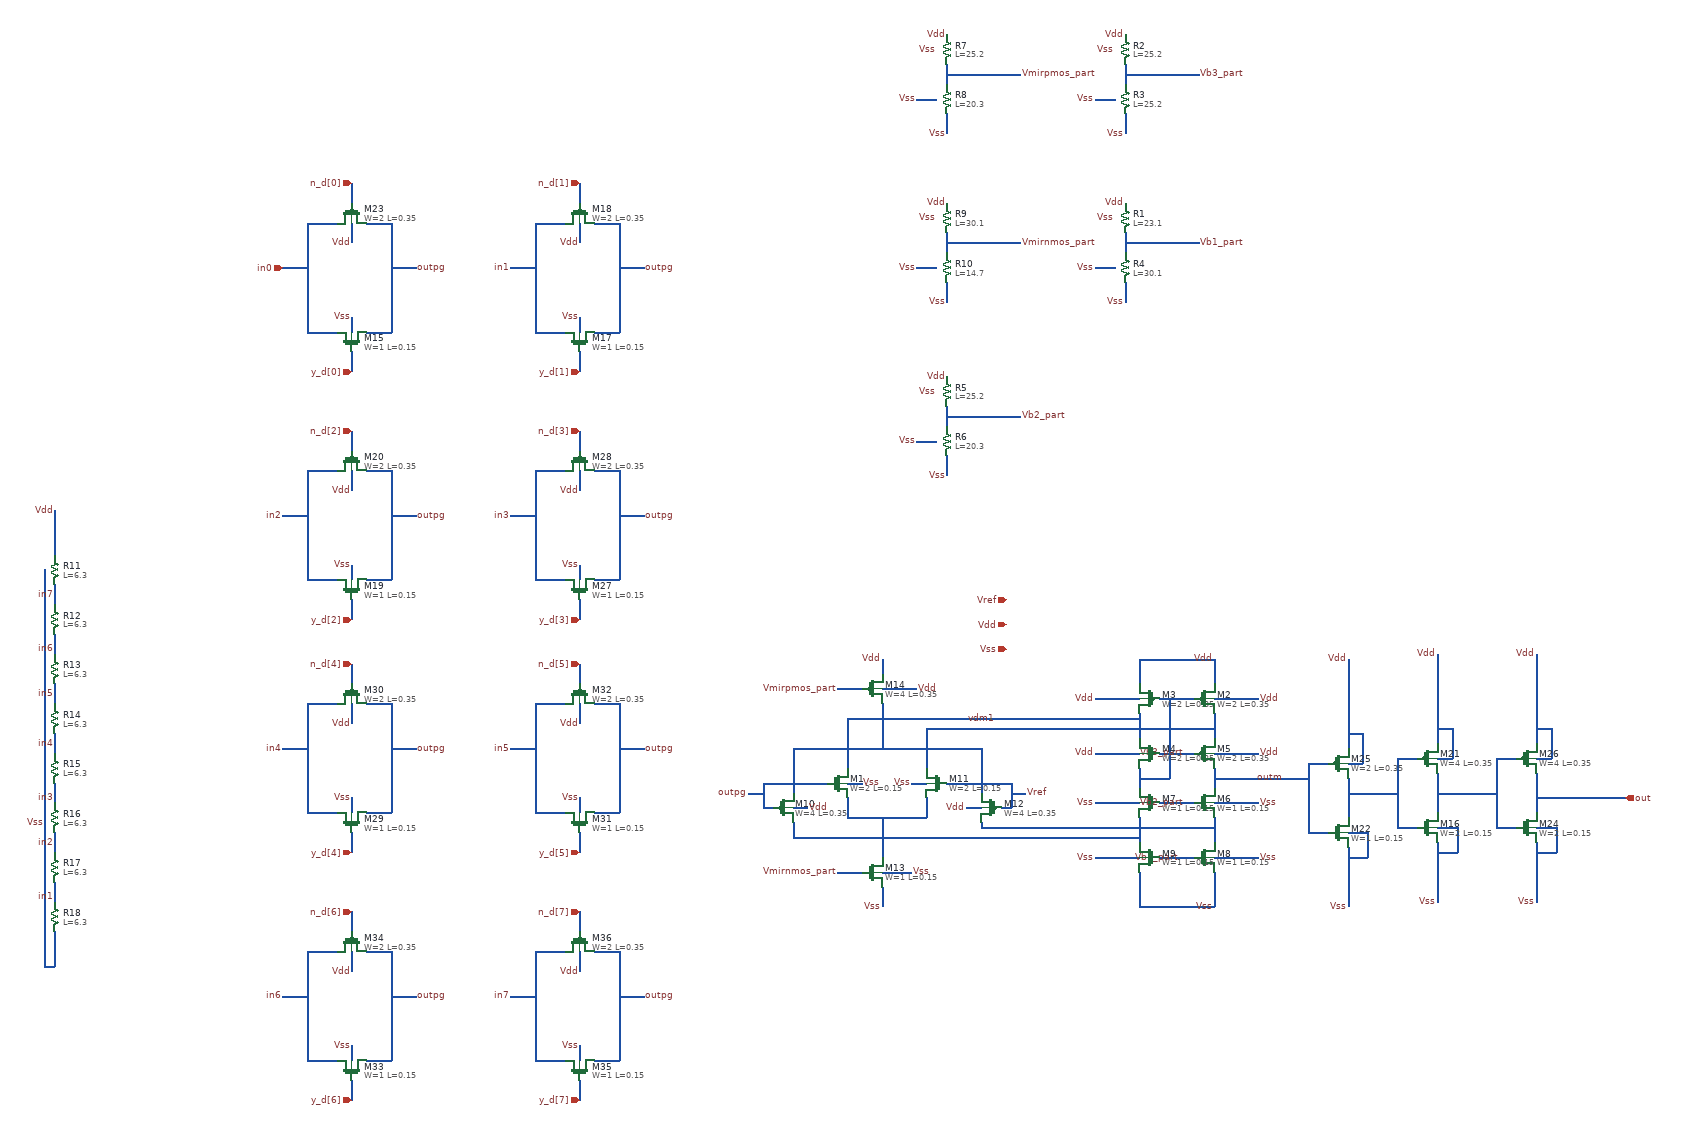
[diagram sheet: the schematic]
v {xschem version=3.4.5 file_version=1.2
}
G {}
K {}
V {}
S {}
E {}
N 430 -90 500 -90 {
lab=Vb1_part}
N 430 -200 500 -200 {
lab=Vb2_part}
N 430 -300 500 -300 {
lab=Vb3_part}
N 430 -410 500 -410 {
lab=#net1}
N 390 -380 390 -330 {
lab=vdm1}
N 390 -270 390 -230 {
lab=#net1}
N 390 -170 390 -120 {
lab=#net2}
N 540 -170 540 -120 {
lab=#net3}
N 540 -270 540 -230 {
lab=outm}
N 540 -380 540 -330 {
lab=#net4}
N 390 -490 390 -440 {
lab=#net5}
N 540 -490 540 -440 {
lab=#net5}
N 390 -60 390 10 {
lab=#net6}
N 540 -60 540 10 {
lab=#net6}
N 390 10 540 10 {
lab=#net6}
N 390 -490 540 -490 {
lab=#net5}
N -310 -310 -310 -220 {
lab=#net7}
N -310 -310 70 -310 {
lab=#net7}
N 70 -310 70 -220 {
lab=#net7}
N -200 -210 -200 -170 {
lab=#net8}
N -200 -170 -40 -170 {
lab=#net8}
N -40 -210 -40 -170 {
lab=#net8}
N -200 -370 390 -370 {
lab=vdm1}
N -200 -370 -200 -270 {
lab=vdm1}
N -40 -350 -40 -270 {
lab=#net4}
N -40 -350 540 -350 {
lab=#net4}
N 70 -160 70 -150 {
lab=#net3}
N 70 -150 540 -150 {
lab=#net3}
N -310 -160 -310 -130 {
lab=#net2}
N -310 -130 390 -130 {
lab=#net2}
N -130 -170 -130 -90 {
lab=#net8}
N -130 -400 -130 -310 {
lab=#net7}
N -130 -490 -130 -460 {
lab=#net9}
N -370 -240 -240 -240 {
lab=outpg}
N -370 -240 -370 -190 {
lab=outpg}
N -370 -190 -350 -190 {
lab=outpg}
N 0 -240 130 -240 {
lab=Vref}
N 130 -240 130 -190 {
lab=Vref}
N 110 -190 130 -190 {
lab=Vref}
N -400 -220 -370 -220 {
lab=outpg}
N 130 -220 160 -220 {
lab=Vref}
N -130 -30 -130 10 {
lab=#net10}
N 390 -250 450 -250 {
lab=#net1}
N 450 -410 450 -250 {
lab=#net1}
N -130 -60 -70 -60 {
lab=Vss}
N -130 -430 -60 -430 {
lab=Vdd}
N 40 -190 70 -190 {
lab=Vdd}
N -70 -240 -40 -240 {
lab=Vss}
N -200 -240 -170 -240 {
lab=Vss}
N -310 -190 -280 -190 {
lab=Vdd}
N 810 -250 810 -170 {
lab=#net11}
N 810 -280 840 -280 {
lab=#net12}
N 810 -140 850 -140 {
lab=#net13}
N 850 -140 850 -90 {
lab=#net13}
N 810 -90 850 -90 {
lab=#net13}
N 730 -280 770 -280 {
lab=outm}
N 730 -280 730 -140 {
lab=outm}
N 730 -140 770 -140 {
lab=outm}
N 840 -340 840 -280 {
lab=#net12}
N 810 -340 840 -340 {
lab=#net12}
N 540 -250 730 -250 {
lab=outm}
N 810 -490 810 -310 {
lab=#net12}
N 810 -110 810 10 {
lab=#net13}
N -220 -60 -170 -60 {
lab=Vmirnmos_part}
N -220 -430 -170 -430 {
lab=Vmirpmos_part}
N 300 -90 390 -90 {
lab=Vss}
N 540 -90 630 -90 {
lab=Vss}
N 300 -200 390 -200 {
lab=Vss}
N 540 -200 630 -200 {
lab=Vss}
N 540 -300 630 -300 {
lab=Vdd}
N 300 -300 390 -300 {
lab=Vdd}
N 300 -410 390 -410 {
lab=Vdd}
N 540 -410 630 -410 {
lab=Vdd}
N 360 -1690 360 -1650 {
lab=Vb3_part}
N 360 -1670 510 -1670 {
lab=Vb3_part}
N 360 -1590 360 -1550 {
lab=#net14}
N 300 -1620 340 -1620 {
lab=Vss}
N 360 -1350 360 -1310 {
lab=Vb1_part}
N 360 -1330 510 -1330 {
lab=Vb1_part}
N 360 -1250 360 -1210 {
lab=#net15}
N 300 -1280 340 -1280 {
lab=Vss}
N 0 -1000 0 -960 {
lab=Vb2_part}
N 0 -980 150 -980 {
lab=Vb2_part}
N 0 -900 0 -860 {
lab=#net16}
N -60 -930 -20 -930 {
lab=Vss}
N 0 -1690 0 -1650 {
lab=Vmirpmos_part}
N 0 -1670 150 -1670 {
lab=Vmirpmos_part}
N 0 -1590 0 -1550 {
lab=#net17}
N -60 -1620 -20 -1620 {
lab=Vss}
N 0 -1350 0 -1310 {
lab=Vmirnmos_part}
N 0 -1330 150 -1330 {
lab=Vmirnmos_part}
N 0 -1250 0 -1210 {
lab=#net18}
N -60 -1280 -20 -1280 {
lab=Vss}
N 990 -260 990 -180 {
lab=#net19}
N 990 -290 1020 -290 {
lab=#net20}
N 990 -150 1030 -150 {
lab=#net21}
N 1030 -150 1030 -100 {
lab=#net21}
N 990 -100 1030 -100 {
lab=#net21}
N 910 -290 950 -290 {
lab=#net11}
N 910 -290 910 -150 {
lab=#net11}
N 910 -150 950 -150 {
lab=#net11}
N 1020 -350 1020 -290 {
lab=#net20}
N 990 -350 1020 -350 {
lab=#net20}
N 990 -500 990 -320 {
lab=#net20}
N 990 -120 990 0 {
lab=#net21}
N 1190 -260 1190 -180 {
lab=out}
N 1190 -290 1220 -290 {
lab=#net22}
N 1190 -150 1230 -150 {
lab=#net23}
N 1230 -150 1230 -100 {
lab=#net23}
N 1190 -100 1230 -100 {
lab=#net23}
N 1110 -290 1150 -290 {
lab=#net19}
N 1110 -290 1110 -150 {
lab=#net19}
N 1110 -150 1150 -150 {
lab=#net19}
N 1220 -350 1220 -290 {
lab=#net22}
N 1190 -350 1220 -350 {
lab=#net22}
N 1190 -500 1190 -320 {
lab=#net22}
N 1190 -120 1190 0 {
lab=#net23}
N 990 -220 1110 -220 {
lab=#net19}
N 810 -220 910 -220 {
lab=#net11}
N 1190 -210 1370 -210 {
lab=out}
N -1800 -40 -1800 0 {
lab=in1}
N -1800 -140 -1800 -100 {
lab=in2}
N -1800 -240 -1800 -200 {
lab=in3}
N -1800 -340 -1800 -300 {
lab=in4}
N -1800 -440 -1800 -400 {
lab=in5}
N -1800 -540 -1800 -500 {
lab=in6}
N -1800 -640 -1800 -600 {
lab=in7}
N -1820 -670 -1820 130 {
lab=Vss}
N -1820 130 -1800 130 {
lab=Vss}
N -1800 60 -1800 130 {
lab=Vss}
N -1800 -790 -1800 -700 {
lab=Vdd}
N -1200 -1180 -1200 -1150 {
lab=Vss}
N -1170 -1370 -1120 -1370 {
lab=outpg}
N -1120 -1320 -1120 -1150 {
lab=outpg}
N -1170 -1150 -1120 -1150 {
lab=outpg}
N -1290 -1370 -1230 -1370 {
lab=in0}
N -1290 -1320 -1290 -1150 {
lab=in0}
N -1290 -1150 -1230 -1150 {
lab=in0}
N -1340 -1280 -1290 -1280 {
lab=in0}
N -1120 -1280 -1070 -1280 {
lab=outpg}
N -1200 -1450 -1200 -1410 {
lab=n_d[0]}
N -1200 -1110 -1200 -1070 {
lab=y_d[0]}
N -1200 -1370 -1200 -1330 {
lab=Vdd}
N -1290 -1370 -1290 -1320 {
lab=in0}
N -1120 -1370 -1120 -1320 {
lab=outpg}
N -740 -1180 -740 -1150 {
lab=Vss}
N -710 -1370 -660 -1370 {
lab=outpg}
N -660 -1320 -660 -1150 {
lab=outpg}
N -710 -1150 -660 -1150 {
lab=outpg}
N -830 -1370 -770 -1370 {
lab=in0}
N -830 -1320 -830 -1150 {
lab=in0}
N -830 -1150 -770 -1150 {
lab=in0}
N -880 -1280 -830 -1280 {
lab=in0}
N -660 -1280 -610 -1280 {
lab=outpg}
N -740 -1450 -740 -1410 {
lab=n_d[1]}
N -740 -1110 -740 -1070 {
lab=y_d[1]}
N -740 -1370 -740 -1330 {
lab=Vdd}
N -830 -1370 -830 -1320 {
lab=in0}
N -660 -1370 -660 -1320 {
lab=outpg}
N -1200 -680 -1200 -650 {
lab=Vss}
N -1170 -870 -1120 -870 {
lab=outpg}
N -1120 -820 -1120 -650 {
lab=outpg}
N -1170 -650 -1120 -650 {
lab=outpg}
N -1290 -870 -1230 -870 {
lab=in0}
N -1290 -820 -1290 -650 {
lab=in0}
N -1290 -650 -1230 -650 {
lab=in0}
N -1340 -780 -1290 -780 {
lab=in0}
N -1120 -780 -1070 -780 {
lab=outpg}
N -1200 -950 -1200 -910 {
lab=n_d[0]}
N -1200 -610 -1200 -570 {
lab=y_d[0]}
N -1200 -870 -1200 -830 {
lab=Vdd}
N -1290 -870 -1290 -820 {
lab=in0}
N -1120 -870 -1120 -820 {
lab=outpg}
N -740 -680 -740 -650 {
lab=Vss}
N -710 -870 -660 -870 {
lab=outpg}
N -660 -820 -660 -650 {
lab=outpg}
N -710 -650 -660 -650 {
lab=outpg}
N -830 -870 -770 -870 {
lab=in0}
N -830 -820 -830 -650 {
lab=in0}
N -830 -650 -770 -650 {
lab=in0}
N -880 -780 -830 -780 {
lab=in0}
N -660 -780 -610 -780 {
lab=outpg}
N -740 -950 -740 -910 {
lab=n_d[1]}
N -740 -610 -740 -570 {
lab=y_d[1]}
N -740 -870 -740 -830 {
lab=Vdd}
N -830 -870 -830 -820 {
lab=in0}
N -660 -870 -660 -820 {
lab=outpg}
N -1200 -210 -1200 -180 {
lab=Vss}
N -1170 -400 -1120 -400 {
lab=outpg}
N -1120 -350 -1120 -180 {
lab=outpg}
N -1170 -180 -1120 -180 {
lab=outpg}
N -1290 -400 -1230 -400 {
lab=in0}
N -1290 -350 -1290 -180 {
lab=in0}
N -1290 -180 -1230 -180 {
lab=in0}
N -1340 -310 -1290 -310 {
lab=in0}
N -1120 -310 -1070 -310 {
lab=outpg}
N -1200 -480 -1200 -440 {
lab=n_d[0]}
N -1200 -140 -1200 -100 {
lab=y_d[0]}
N -1200 -400 -1200 -360 {
lab=Vdd}
N -1290 -400 -1290 -350 {
lab=in0}
N -1120 -400 -1120 -350 {
lab=outpg}
N -740 -210 -740 -180 {
lab=Vss}
N -710 -400 -660 -400 {
lab=outpg}
N -660 -350 -660 -180 {
lab=outpg}
N -710 -180 -660 -180 {
lab=outpg}
N -830 -400 -770 -400 {
lab=in0}
N -830 -350 -830 -180 {
lab=in0}
N -830 -180 -770 -180 {
lab=in0}
N -880 -310 -830 -310 {
lab=in0}
N -660 -310 -610 -310 {
lab=outpg}
N -740 -480 -740 -440 {
lab=n_d[1]}
N -740 -140 -740 -100 {
lab=y_d[1]}
N -740 -400 -740 -360 {
lab=Vdd}
N -830 -400 -830 -350 {
lab=in0}
N -660 -400 -660 -350 {
lab=outpg}
N -1200 290 -1200 320 {
lab=Vss}
N -1170 100 -1120 100 {
lab=outpg}
N -1120 150 -1120 320 {
lab=outpg}
N -1170 320 -1120 320 {
lab=outpg}
N -1290 100 -1230 100 {
lab=in0}
N -1290 150 -1290 320 {
lab=in0}
N -1290 320 -1230 320 {
lab=in0}
N -1340 190 -1290 190 {
lab=in0}
N -1120 190 -1070 190 {
lab=outpg}
N -1200 20 -1200 60 {
lab=n_d[0]}
N -1200 360 -1200 400 {
lab=y_d[0]}
N -1200 100 -1200 140 {
lab=Vdd}
N -1290 100 -1290 150 {
lab=in0}
N -1120 100 -1120 150 {
lab=outpg}
N -740 290 -740 320 {
lab=Vss}
N -710 100 -660 100 {
lab=outpg}
N -660 150 -660 320 {
lab=outpg}
N -710 320 -660 320 {
lab=outpg}
N -830 100 -770 100 {
lab=in0}
N -830 150 -830 320 {
lab=in0}
N -830 320 -770 320 {
lab=in0}
N -880 190 -830 190 {
lab=in0}
N -660 190 -610 190 {
lab=outpg}
N -740 20 -740 60 {
lab=n_d[1]}
N -740 360 -740 400 {
lab=y_d[1]}
N -740 100 -740 140 {
lab=Vdd}
N -830 100 -830 150 {
lab=in0}
N -660 100 -660 150 {
lab=outpg}
C {sky130_fd_pr/nfet_01v8_lvt.sym} -220 -240 0 0 {name=M1
L=0.15
W=2
nf=2
mult=1
ad="'int((nf+1)/2) * W/nf * 0.29'" 
pd="'2*int((nf+1)/2) * (W/nf + 0.29)'"
as="'int((nf+2)/2) * W/nf * 0.29'" 
ps="'2*int((nf+2)/2) * (W/nf + 0.29)'"
nrd="'0.29 / W'" nrs="'0.29 / W'"
sa=0 sb=0 sd=0
model=nfet_01v8_lvt
spiceprefix=X
}
C {sky130_fd_pr/pfet_01v8_lvt.sym} 410 -410 0 1 {name=M3
L=0.35
W=2
nf=2
mult=1
ad="'int((nf+1)/2) * W/nf * 0.29'" 
pd="'2*int((nf+1)/2) * (W/nf + 0.29)'"
as="'int((nf+2)/2) * W/nf * 0.29'" 
ps="'2*int((nf+2)/2) * (W/nf + 0.29)'"
nrd="'0.29 / W'" nrs="'0.29 / W'"
sa=0 sb=0 sd=0
model=pfet_01v8_lvt
spiceprefix=X
}
C {sky130_fd_pr/nfet_01v8_lvt.sym} 410 -200 0 1 {name=M7
L=0.15
W=1
nf=1
mult=1
ad="'int((nf+1)/2) * W/nf * 0.29'" 
pd="'2*int((nf+1)/2) * (W/nf + 0.29)'"
as="'int((nf+2)/2) * W/nf * 0.29'" 
ps="'2*int((nf+2)/2) * (W/nf + 0.29)'"
nrd="'0.29 / W'" nrs="'0.29 / W'"
sa=0 sb=0 sd=0
model=nfet_01v8_lvt
spiceprefix=X
}
C {devices/lab_wire.sym} 300 -300 0 0 {name=p1 sig_type=std_logic lab=Vdd}
C {devices/lab_wire.sym} 300 -410 0 0 {name=p2 sig_type=std_logic lab=Vdd}
C {devices/lab_wire.sym} 630 -410 0 1 {name=p3 sig_type=std_logic lab=Vdd}
C {devices/lab_wire.sym} 630 -300 0 1 {name=p4 sig_type=std_logic lab=Vdd}
C {devices/lab_wire.sym} 300 -200 0 0 {name=p5 sig_type=std_logic lab=Vss}
C {devices/lab_wire.sym} 300 -90 0 0 {name=p6 sig_type=std_logic lab=Vss}
C {devices/lab_wire.sym} 630 -90 0 1 {name=p7 sig_type=std_logic lab=Vss}
C {devices/lab_wire.sym} 630 -200 0 1 {name=p8 sig_type=std_logic lab=Vss}
C {devices/lab_wire.sym} 480 -300 0 0 {name=p13 sig_type=std_logic lab=Vb3_part}
C {devices/lab_wire.sym} 480 -200 0 0 {name=p14 sig_type=std_logic lab=Vb2_part}
C {devices/lab_wire.sym} 470 -90 0 0 {name=p16 sig_type=std_logic lab=Vb1_part}
C {devices/lab_wire.sym} 540 10 0 0 {name=p17 sig_type=std_logic lab=Vss}
C {devices/lab_wire.sym} 540 -490 0 0 {name=p18 sig_type=std_logic lab=Vdd}
C {sky130_fd_pr/pfet_01v8_lvt.sym} -330 -190 0 0 {name=M10
L=0.35
W=4
nf=4
mult=1
ad="'int((nf+1)/2) * W/nf * 0.29'" 
pd="'2*int((nf+1)/2) * (W/nf + 0.29)'"
as="'int((nf+2)/2) * W/nf * 0.29'" 
ps="'2*int((nf+2)/2) * (W/nf + 0.29)'"
nrd="'0.29 / W'" nrs="'0.29 / W'"
sa=0 sb=0 sd=0
model=pfet_01v8_lvt
spiceprefix=X
}
C {sky130_fd_pr/nfet_01v8_lvt.sym} -20 -240 0 1 {name=M11
L=0.15
W=2
nf=2
mult=1
ad="'int((nf+1)/2) * W/nf * 0.29'" 
pd="'2*int((nf+1)/2) * (W/nf + 0.29)'"
as="'int((nf+2)/2) * W/nf * 0.29'" 
ps="'2*int((nf+2)/2) * (W/nf + 0.29)'"
nrd="'0.29 / W'" nrs="'0.29 / W'"
sa=0 sb=0 sd=0
model=nfet_01v8_lvt
spiceprefix=X
}
C {sky130_fd_pr/pfet_01v8_lvt.sym} 90 -190 0 1 {name=M12
L=0.35
W=4
nf=4
mult=1
ad="'int((nf+1)/2) * W/nf * 0.29'" 
pd="'2*int((nf+1)/2) * (W/nf + 0.29)'"
as="'int((nf+2)/2) * W/nf * 0.29'" 
ps="'2*int((nf+2)/2) * (W/nf + 0.29)'"
nrd="'0.29 / W'" nrs="'0.29 / W'"
sa=0 sb=0 sd=0
model=pfet_01v8_lvt
spiceprefix=X
}
C {sky130_fd_pr/nfet_01v8_lvt.sym} -150 -60 0 0 {name=M13
L=0.15
W=1
nf=1
mult=1
ad="'int((nf+1)/2) * W/nf * 0.29'" 
pd="'2*int((nf+1)/2) * (W/nf + 0.29)'"
as="'int((nf+2)/2) * W/nf * 0.29'" 
ps="'2*int((nf+2)/2) * (W/nf + 0.29)'"
nrd="'0.29 / W'" nrs="'0.29 / W'"
sa=0 sb=0 sd=0
model=nfet_01v8_lvt
spiceprefix=X
}
C {sky130_fd_pr/pfet_01v8_lvt.sym} -150 -430 0 0 {name=M14
L=0.35
W=4
nf=4
mult=1
ad="'int((nf+1)/2) * W/nf * 0.29'" 
pd="'2*int((nf+1)/2) * (W/nf + 0.29)'"
as="'int((nf+2)/2) * W/nf * 0.29'" 
ps="'2*int((nf+2)/2) * (W/nf + 0.29)'"
nrd="'0.29 / W'" nrs="'0.29 / W'"
sa=0 sb=0 sd=0
model=pfet_01v8_lvt
spiceprefix=X
}
C {devices/lab_wire.sym} -130 -490 0 0 {name=p19 sig_type=std_logic lab=Vdd}
C {devices/lab_wire.sym} -130 10 0 0 {name=p20 sig_type=std_logic lab=Vss}
C {devices/lab_wire.sym} 160 -220 0 1 {name=p22 sig_type=std_logic lab=Vref}
C {devices/opin.sym} 1370 -210 0 0 {name=p24 lab=out}
C {devices/lab_wire.sym} -60 -430 0 1 {name=p26 sig_type=std_logic lab=Vdd}
C {devices/lab_wire.sym} -70 -60 0 1 {name=p28 sig_type=std_logic lab=Vss}
C {devices/lab_wire.sym} -170 -240 0 1 {name=p29 sig_type=std_logic lab=Vss}
C {devices/lab_wire.sym} -70 -240 0 0 {name=p30 sig_type=std_logic lab=Vss}
C {devices/lab_wire.sym} -280 -190 0 1 {name=p31 sig_type=std_logic lab=Vdd}
C {devices/lab_wire.sym} 40 -190 0 0 {name=p32 sig_type=std_logic lab=Vdd}
C {sky130_fd_pr/nfet_01v8_lvt.sym} 790 -140 0 0 {name=M22
L=0.15
W=1
nf=1
mult=1
ad="'int((nf+1)/2) * W/nf * 0.29'" 
pd="'2*int((nf+1)/2) * (W/nf + 0.29)'"
as="'int((nf+2)/2) * W/nf * 0.29'" 
ps="'2*int((nf+2)/2) * (W/nf + 0.29)'"
nrd="'0.29 / W'" nrs="'0.29 / W'"
sa=0 sb=0 sd=0
model=nfet_01v8_lvt
spiceprefix=X
}
C {sky130_fd_pr/pfet_01v8_lvt.sym} 790 -280 0 0 {name=M25
L=0.35
W=2
nf=2
mult=1
ad="'int((nf+1)/2) * W/nf * 0.29'" 
pd="'2*int((nf+1)/2) * (W/nf + 0.29)'"
as="'int((nf+2)/2) * W/nf * 0.29'" 
ps="'2*int((nf+2)/2) * (W/nf + 0.29)'"
nrd="'0.29 / W'" nrs="'0.29 / W'"
sa=0 sb=0 sd=0
model=pfet_01v8_lvt
spiceprefix=X
}
C {devices/lab_wire.sym} 680 -250 0 0 {name=p9 sig_type=std_logic lab=outm}
C {devices/lab_wire.sym} 100 -370 0 0 {name=p37 sig_type=std_logic lab=vdm1}
C {devices/lab_wire.sym} -220 -430 0 0 {name=p39 sig_type=std_logic lab=Vmirpmos_part}
C {devices/lab_wire.sym} -220 -60 0 0 {name=p41 sig_type=std_logic lab=Vmirnmos_part}
C {sky130_fd_pr/res_high_po_0p35.sym} 360 -1720 0 0 {name=R2
L=25.2
model=res_high_po_0p35
spiceprefix=X
mult=1}
C {devices/lab_wire.sym} 340 -1720 0 0 {name=p35 sig_type=std_logic lab=Vss}
C {devices/lab_wire.sym} 360 -1750 0 0 {name=p36 sig_type=std_logic lab=Vdd}
C {devices/lab_wire.sym} 510 -1670 0 1 {name=p42 sig_type=std_logic lab=Vb3_part}
C {devices/lab_wire.sym} 360 -1550 3 0 {name=p43 sig_type=std_logic lab=Vss}
C {devices/lab_wire.sym} 300 -1620 0 0 {name=p55 sig_type=std_logic lab=Vss}
C {sky130_fd_pr/res_high_po_0p35.sym} 360 -1620 0 0 {name=R3
L=25.2
model=res_high_po_0p35
spiceprefix=X
mult=1}
C {sky130_fd_pr/res_high_po_0p35.sym} 360 -1380 0 0 {name=R1
L=23.1
model=res_high_po_0p35
spiceprefix=X
mult=1}
C {devices/lab_wire.sym} 340 -1380 0 0 {name=p23 sig_type=std_logic lab=Vss}
C {devices/lab_wire.sym} 360 -1410 0 0 {name=p25 sig_type=std_logic lab=Vdd}
C {devices/lab_wire.sym} 510 -1330 0 1 {name=p27 sig_type=std_logic lab=Vb1_part}
C {devices/lab_wire.sym} 360 -1210 3 0 {name=p33 sig_type=std_logic lab=Vss}
C {devices/lab_wire.sym} 300 -1280 0 0 {name=p34 sig_type=std_logic lab=Vss}
C {sky130_fd_pr/res_high_po_0p35.sym} 360 -1280 0 0 {name=R4
L=30.1
model=res_high_po_0p35
spiceprefix=X
mult=1}
C {sky130_fd_pr/res_high_po_0p35.sym} 0 -1030 0 0 {name=R5
L=25.2
model=res_high_po_0p35
spiceprefix=X
mult=1}
C {devices/lab_wire.sym} -20 -1030 0 0 {name=p56 sig_type=std_logic lab=Vss}
C {devices/lab_wire.sym} 0 -1060 0 0 {name=p58 sig_type=std_logic lab=Vdd}
C {devices/lab_wire.sym} 150 -980 0 1 {name=p59 sig_type=std_logic lab=Vb2_part}
C {devices/lab_wire.sym} 0 -860 3 0 {name=p60 sig_type=std_logic lab=Vss}
C {devices/lab_wire.sym} -60 -930 0 0 {name=p61 sig_type=std_logic lab=Vss}
C {sky130_fd_pr/res_high_po_0p35.sym} 0 -930 0 0 {name=R6
L=20.3
model=res_high_po_0p35
spiceprefix=X
mult=1}
C {sky130_fd_pr/res_high_po_0p35.sym} 0 -1720 0 0 {name=R7
L=25.2
model=res_high_po_0p35
spiceprefix=X
mult=1}
C {devices/lab_wire.sym} -20 -1720 0 0 {name=p62 sig_type=std_logic lab=Vss}
C {devices/lab_wire.sym} 0 -1750 0 0 {name=p63 sig_type=std_logic lab=Vdd}
C {devices/lab_wire.sym} 150 -1670 0 1 {name=p64 sig_type=std_logic lab=Vmirpmos_part}
C {devices/lab_wire.sym} 0 -1550 3 0 {name=p65 sig_type=std_logic lab=Vss}
C {devices/lab_wire.sym} -60 -1620 0 0 {name=p66 sig_type=std_logic lab=Vss}
C {sky130_fd_pr/res_high_po_0p35.sym} 0 -1620 0 0 {name=R8
L=20.3
model=res_high_po_0p35
spiceprefix=X
mult=1}
C {sky130_fd_pr/res_high_po_0p35.sym} 0 -1380 0 0 {name=R9
L=30.1
model=res_high_po_0p35
spiceprefix=X
mult=1}
C {devices/lab_wire.sym} -20 -1380 0 0 {name=p67 sig_type=std_logic lab=Vss}
C {devices/lab_wire.sym} 0 -1410 0 0 {name=p68 sig_type=std_logic lab=Vdd}
C {devices/lab_wire.sym} 150 -1330 0 1 {name=p69 sig_type=std_logic lab=Vmirnmos_part}
C {devices/lab_wire.sym} 0 -1210 3 0 {name=p70 sig_type=std_logic lab=Vss}
C {devices/lab_wire.sym} -60 -1280 0 0 {name=p71 sig_type=std_logic lab=Vss}
C {sky130_fd_pr/res_high_po_0p35.sym} 0 -1280 0 0 {name=R10
L=14.7
model=res_high_po_0p35
spiceprefix=X
mult=1}
C {devices/lab_wire.sym} 810 -490 0 0 {name=p74 sig_type=std_logic lab=Vdd}
C {devices/lab_wire.sym} 810 10 0 0 {name=p75 sig_type=std_logic lab=Vss}
C {devices/lab_wire.sym} -400 -220 0 0 {name=p79 sig_type=std_logic lab=outpg}
C {sky130_fd_pr/nfet_01v8_lvt.sym} 970 -150 0 0 {name=M16
L=0.15
W=2
nf=2
mult=1
ad="'int((nf+1)/2) * W/nf * 0.29'" 
pd="'2*int((nf+1)/2) * (W/nf + 0.29)'"
as="'int((nf+2)/2) * W/nf * 0.29'" 
ps="'2*int((nf+2)/2) * (W/nf + 0.29)'"
nrd="'0.29 / W'" nrs="'0.29 / W'"
sa=0 sb=0 sd=0
model=nfet_01v8_lvt
spiceprefix=X
}
C {sky130_fd_pr/pfet_01v8_lvt.sym} 970 -290 0 0 {name=M21
L=0.35
W=4
nf=4
mult=1
ad="'int((nf+1)/2) * W/nf * 0.29'" 
pd="'2*int((nf+1)/2) * (W/nf + 0.29)'"
as="'int((nf+2)/2) * W/nf * 0.29'" 
ps="'2*int((nf+2)/2) * (W/nf + 0.29)'"
nrd="'0.29 / W'" nrs="'0.29 / W'"
sa=0 sb=0 sd=0
model=pfet_01v8_lvt
spiceprefix=X
}
C {devices/lab_wire.sym} 990 0 0 0 {name=p85 sig_type=std_logic lab=Vss}
C {sky130_fd_pr/nfet_01v8_lvt.sym} 1170 -150 0 0 {name=M24
L=0.15
W=2
nf=2
mult=1
ad="'int((nf+1)/2) * W/nf * 0.29'" 
pd="'2*int((nf+1)/2) * (W/nf + 0.29)'"
as="'int((nf+2)/2) * W/nf * 0.29'" 
ps="'2*int((nf+2)/2) * (W/nf + 0.29)'"
nrd="'0.29 / W'" nrs="'0.29 / W'"
sa=0 sb=0 sd=0
model=nfet_01v8_lvt
spiceprefix=X
}
C {sky130_fd_pr/pfet_01v8_lvt.sym} 1170 -290 0 0 {name=M26
L=0.35
W=4
nf=4
mult=1
ad="'int((nf+1)/2) * W/nf * 0.29'" 
pd="'2*int((nf+1)/2) * (W/nf + 0.29)'"
as="'int((nf+2)/2) * W/nf * 0.29'" 
ps="'2*int((nf+2)/2) * (W/nf + 0.29)'"
nrd="'0.29 / W'" nrs="'0.29 / W'"
sa=0 sb=0 sd=0
model=pfet_01v8_lvt
spiceprefix=X
}
C {devices/lab_wire.sym} 1190 0 0 0 {name=p88 sig_type=std_logic lab=Vss}
C {devices/lab_wire.sym} 990 -500 0 0 {name=p57 sig_type=std_logic lab=Vdd}
C {devices/lab_wire.sym} 1190 -500 0 0 {name=p89 sig_type=std_logic lab=Vdd}
C {sky130_fd_pr/pfet_01v8_lvt.sym} 520 -410 0 0 {name=M2
L=0.35
W=2
nf=2
mult=1
ad="'int((nf+1)/2) * W/nf * 0.29'" 
pd="'2*int((nf+1)/2) * (W/nf + 0.29)'"
as="'int((nf+2)/2) * W/nf * 0.29'" 
ps="'2*int((nf+2)/2) * (W/nf + 0.29)'"
nrd="'0.29 / W'" nrs="'0.29 / W'"
sa=0 sb=0 sd=0
model=pfet_01v8_lvt
spiceprefix=X
}
C {sky130_fd_pr/pfet_01v8_lvt.sym} 410 -300 0 1 {name=M4
L=0.35
W=2
nf=2
mult=1
ad="'int((nf+1)/2) * W/nf * 0.29'" 
pd="'2*int((nf+1)/2) * (W/nf + 0.29)'"
as="'int((nf+2)/2) * W/nf * 0.29'" 
ps="'2*int((nf+2)/2) * (W/nf + 0.29)'"
nrd="'0.29 / W'" nrs="'0.29 / W'"
sa=0 sb=0 sd=0
model=pfet_01v8_lvt
spiceprefix=X
}
C {sky130_fd_pr/pfet_01v8_lvt.sym} 520 -300 0 0 {name=M5
L=0.35
W=2
nf=2
mult=1
ad="'int((nf+1)/2) * W/nf * 0.29'" 
pd="'2*int((nf+1)/2) * (W/nf + 0.29)'"
as="'int((nf+2)/2) * W/nf * 0.29'" 
ps="'2*int((nf+2)/2) * (W/nf + 0.29)'"
nrd="'0.29 / W'" nrs="'0.29 / W'"
sa=0 sb=0 sd=0
model=pfet_01v8_lvt
spiceprefix=X
}
C {sky130_fd_pr/nfet_01v8_lvt.sym} 520 -200 0 0 {name=M6
L=0.15
W=1
nf=1
mult=1
ad="'int((nf+1)/2) * W/nf * 0.29'" 
pd="'2*int((nf+1)/2) * (W/nf + 0.29)'"
as="'int((nf+2)/2) * W/nf * 0.29'" 
ps="'2*int((nf+2)/2) * (W/nf + 0.29)'"
nrd="'0.29 / W'" nrs="'0.29 / W'"
sa=0 sb=0 sd=0
model=nfet_01v8_lvt
spiceprefix=X
}
C {sky130_fd_pr/nfet_01v8_lvt.sym} 520 -90 0 0 {name=M8
L=0.15
W=1
nf=1
mult=1
ad="'int((nf+1)/2) * W/nf * 0.29'" 
pd="'2*int((nf+1)/2) * (W/nf + 0.29)'"
as="'int((nf+2)/2) * W/nf * 0.29'" 
ps="'2*int((nf+2)/2) * (W/nf + 0.29)'"
nrd="'0.29 / W'" nrs="'0.29 / W'"
sa=0 sb=0 sd=0
model=nfet_01v8_lvt
spiceprefix=X
}
C {sky130_fd_pr/nfet_01v8_lvt.sym} 410 -90 0 1 {name=M9
L=0.15
W=1
nf=1
mult=1
ad="'int((nf+1)/2) * W/nf * 0.29'" 
pd="'2*int((nf+1)/2) * (W/nf + 0.29)'"
as="'int((nf+2)/2) * W/nf * 0.29'" 
ps="'2*int((nf+2)/2) * (W/nf + 0.29)'"
nrd="'0.29 / W'" nrs="'0.29 / W'"
sa=0 sb=0 sd=0
model=nfet_01v8_lvt
spiceprefix=X
}
C {devices/ipin.sym} 120 -560 0 0 {name=p10 lab=Vdd}
C {devices/ipin.sym} 120 -510 0 0 {name=p11 lab=Vss}
C {devices/lab_wire.sym} -1820 -160 0 0 {name=p95 sig_type=std_logic lab=Vss}
C {devices/lab_wire.sym} -1800 -790 0 0 {name=p97 sig_type=std_logic lab=Vdd}
C {devices/lab_wire.sym} -1800 -10 0 0 {name=p103 sig_type=std_logic lab=in1}
C {devices/lab_wire.sym} -1800 -120 0 0 {name=p104 sig_type=std_logic lab=in2
}
C {devices/lab_wire.sym} -1800 -210 0 0 {name=p105 sig_type=std_logic lab=in3}
C {devices/lab_wire.sym} -1800 -320 0 0 {name=p106 sig_type=std_logic lab=in4}
C {devices/lab_wire.sym} -1800 -420 0 0 {name=p107 sig_type=std_logic lab=in5}
C {devices/lab_wire.sym} -1800 -510 0 0 {name=p108 sig_type=std_logic lab=in6}
C {devices/lab_wire.sym} -1800 -620 0 0 {name=p109 sig_type=std_logic lab=in7}
C {sky130_fd_pr/res_high_po_0p35.sym} -1800 -670 0 0 {name=R11
L=6.3
model=res_high_po_0p35
spiceprefix=X
mult=1}
C {sky130_fd_pr/res_high_po_0p35.sym} -1800 -570 0 0 {name=R12
L=6.3
model=res_high_po_0p35
spiceprefix=X
mult=1}
C {sky130_fd_pr/res_high_po_0p35.sym} -1800 -470 0 0 {name=R13
L=6.3
model=res_high_po_0p35
spiceprefix=X
mult=1}
C {sky130_fd_pr/res_high_po_0p35.sym} -1800 -370 0 0 {name=R14
L=6.3
model=res_high_po_0p35
spiceprefix=X
mult=1}
C {sky130_fd_pr/res_high_po_0p35.sym} -1800 -270 0 0 {name=R15
L=6.3
model=res_high_po_0p35
spiceprefix=X
mult=1}
C {sky130_fd_pr/res_high_po_0p35.sym} -1800 -170 0 0 {name=R16
L=6.3
model=res_high_po_0p35
spiceprefix=X
mult=1}
C {sky130_fd_pr/res_high_po_0p35.sym} -1800 -70 0 0 {name=R17
L=6.3
model=res_high_po_0p35
spiceprefix=X
mult=1}
C {sky130_fd_pr/res_high_po_0p35.sym} -1800 30 0 0 {name=R18
L=6.3
model=res_high_po_0p35
spiceprefix=X
mult=1}
C {devices/ipin.sym} 120 -610 0 0 {name=p12 lab=Vref}
C {sky130_fd_pr/nfet_01v8_lvt.sym} -1200 -1130 3 0 {name=M15
L=0.15
W=1
nf=1
mult=1
ad="'int((nf+1)/2) * W/nf * 0.29'" 
pd="'2*int((nf+1)/2) * (W/nf + 0.29)'"
as="'int((nf+2)/2) * W/nf * 0.29'" 
ps="'2*int((nf+2)/2) * (W/nf + 0.29)'"
nrd="'0.29 / W'" nrs="'0.29 / W'"
sa=0 sb=0 sd=0
model=nfet_01v8_lvt
spiceprefix=X
}
C {sky130_fd_pr/pfet_01v8_lvt.sym} -1200 -1390 3 1 {name=M23
L=0.35
W=2
nf=2
mult=1
ad="'int((nf+1)/2) * W/nf * 0.29'" 
pd="'2*int((nf+1)/2) * (W/nf + 0.29)'"
as="'int((nf+2)/2) * W/nf * 0.29'" 
ps="'2*int((nf+2)/2) * (W/nf + 0.29)'"
nrd="'0.29 / W'" nrs="'0.29 / W'"
sa=0 sb=0 sd=0
model=pfet_01v8_lvt
spiceprefix=X
}
C {devices/ipin.sym} -1200 -1450 0 0 {name=p111 lab=n_d[0]}
C {devices/ipin.sym} -1200 -1070 0 0 {name=p114 lab=y_d[0]}
C {devices/ipin.sym} -1340 -1280 0 0 {name=p38 lab=in0}
C {sky130_fd_pr/nfet_01v8_lvt.sym} -740 -1130 3 0 {name=M17
L=0.15
W=1
nf=1
mult=1
ad="'int((nf+1)/2) * W/nf * 0.29'" 
pd="'2*int((nf+1)/2) * (W/nf + 0.29)'"
as="'int((nf+2)/2) * W/nf * 0.29'" 
ps="'2*int((nf+2)/2) * (W/nf + 0.29)'"
nrd="'0.29 / W'" nrs="'0.29 / W'"
sa=0 sb=0 sd=0
model=nfet_01v8_lvt
spiceprefix=X
}
C {sky130_fd_pr/pfet_01v8_lvt.sym} -740 -1390 3 1 {name=M18
L=0.35
W=2
nf=2
mult=1
ad="'int((nf+1)/2) * W/nf * 0.29'" 
pd="'2*int((nf+1)/2) * (W/nf + 0.29)'"
as="'int((nf+2)/2) * W/nf * 0.29'" 
ps="'2*int((nf+2)/2) * (W/nf + 0.29)'"
nrd="'0.29 / W'" nrs="'0.29 / W'"
sa=0 sb=0 sd=0
model=pfet_01v8_lvt
spiceprefix=X
}
C {devices/ipin.sym} -740 -1450 0 0 {name=p44 lab=n_d[1]}
C {devices/ipin.sym} -740 -1070 0 0 {name=p45 lab=y_d[1]}
C {sky130_fd_pr/nfet_01v8_lvt.sym} -1200 -630 3 0 {name=M19
L=0.15
W=1
nf=1
mult=1
ad="'int((nf+1)/2) * W/nf * 0.29'" 
pd="'2*int((nf+1)/2) * (W/nf + 0.29)'"
as="'int((nf+2)/2) * W/nf * 0.29'" 
ps="'2*int((nf+2)/2) * (W/nf + 0.29)'"
nrd="'0.29 / W'" nrs="'0.29 / W'"
sa=0 sb=0 sd=0
model=nfet_01v8_lvt
spiceprefix=X
}
C {sky130_fd_pr/pfet_01v8_lvt.sym} -1200 -890 3 1 {name=M20
L=0.35
W=2
nf=2
mult=1
ad="'int((nf+1)/2) * W/nf * 0.29'" 
pd="'2*int((nf+1)/2) * (W/nf + 0.29)'"
as="'int((nf+2)/2) * W/nf * 0.29'" 
ps="'2*int((nf+2)/2) * (W/nf + 0.29)'"
nrd="'0.29 / W'" nrs="'0.29 / W'"
sa=0 sb=0 sd=0
model=pfet_01v8_lvt
spiceprefix=X
}
C {devices/ipin.sym} -1200 -950 0 0 {name=p50 lab=n_d[2]}
C {devices/ipin.sym} -1200 -570 0 0 {name=p51 lab=y_d[2]}
C {sky130_fd_pr/nfet_01v8_lvt.sym} -740 -630 3 0 {name=M27
L=0.15
W=1
nf=1
mult=1
ad="'int((nf+1)/2) * W/nf * 0.29'" 
pd="'2*int((nf+1)/2) * (W/nf + 0.29)'"
as="'int((nf+2)/2) * W/nf * 0.29'" 
ps="'2*int((nf+2)/2) * (W/nf + 0.29)'"
nrd="'0.29 / W'" nrs="'0.29 / W'"
sa=0 sb=0 sd=0
model=nfet_01v8_lvt
spiceprefix=X
}
C {sky130_fd_pr/pfet_01v8_lvt.sym} -740 -890 3 1 {name=M28
L=0.35
W=2
nf=2
mult=1
ad="'int((nf+1)/2) * W/nf * 0.29'" 
pd="'2*int((nf+1)/2) * (W/nf + 0.29)'"
as="'int((nf+2)/2) * W/nf * 0.29'" 
ps="'2*int((nf+2)/2) * (W/nf + 0.29)'"
nrd="'0.29 / W'" nrs="'0.29 / W'"
sa=0 sb=0 sd=0
model=pfet_01v8_lvt
spiceprefix=X
}
C {devices/ipin.sym} -740 -950 0 0 {name=p73 lab=n_d[3]}
C {devices/ipin.sym} -740 -570 0 0 {name=p76 lab=y_d[3]}
C {sky130_fd_pr/nfet_01v8_lvt.sym} -1200 -160 3 0 {name=M29
L=0.15
W=1
nf=1
mult=1
ad="'int((nf+1)/2) * W/nf * 0.29'" 
pd="'2*int((nf+1)/2) * (W/nf + 0.29)'"
as="'int((nf+2)/2) * W/nf * 0.29'" 
ps="'2*int((nf+2)/2) * (W/nf + 0.29)'"
nrd="'0.29 / W'" nrs="'0.29 / W'"
sa=0 sb=0 sd=0
model=nfet_01v8_lvt
spiceprefix=X
}
C {sky130_fd_pr/pfet_01v8_lvt.sym} -1200 -420 3 1 {name=M30
L=0.35
W=2
nf=2
mult=1
ad="'int((nf+1)/2) * W/nf * 0.29'" 
pd="'2*int((nf+1)/2) * (W/nf + 0.29)'"
as="'int((nf+2)/2) * W/nf * 0.29'" 
ps="'2*int((nf+2)/2) * (W/nf + 0.29)'"
nrd="'0.29 / W'" nrs="'0.29 / W'"
sa=0 sb=0 sd=0
model=pfet_01v8_lvt
spiceprefix=X
}
C {devices/ipin.sym} -1200 -480 0 0 {name=p82 lab=n_d[4]}
C {devices/ipin.sym} -1200 -100 0 0 {name=p83 lab=y_d[4]}
C {sky130_fd_pr/nfet_01v8_lvt.sym} -740 -160 3 0 {name=M31
L=0.15
W=1
nf=1
mult=1
ad="'int((nf+1)/2) * W/nf * 0.29'" 
pd="'2*int((nf+1)/2) * (W/nf + 0.29)'"
as="'int((nf+2)/2) * W/nf * 0.29'" 
ps="'2*int((nf+2)/2) * (W/nf + 0.29)'"
nrd="'0.29 / W'" nrs="'0.29 / W'"
sa=0 sb=0 sd=0
model=nfet_01v8_lvt
spiceprefix=X
}
C {sky130_fd_pr/pfet_01v8_lvt.sym} -740 -420 3 1 {name=M32
L=0.35
W=2
nf=2
mult=1
ad="'int((nf+1)/2) * W/nf * 0.29'" 
pd="'2*int((nf+1)/2) * (W/nf + 0.29)'"
as="'int((nf+2)/2) * W/nf * 0.29'" 
ps="'2*int((nf+2)/2) * (W/nf + 0.29)'"
nrd="'0.29 / W'" nrs="'0.29 / W'"
sa=0 sb=0 sd=0
model=pfet_01v8_lvt
spiceprefix=X
}
C {devices/ipin.sym} -740 -480 0 0 {name=p91 lab=n_d[5]}
C {devices/ipin.sym} -740 -100 0 0 {name=p92 lab=y_d[5]}
C {sky130_fd_pr/nfet_01v8_lvt.sym} -1200 340 3 0 {name=M33
L=0.15
W=1
nf=1
mult=1
ad="'int((nf+1)/2) * W/nf * 0.29'" 
pd="'2*int((nf+1)/2) * (W/nf + 0.29)'"
as="'int((nf+2)/2) * W/nf * 0.29'" 
ps="'2*int((nf+2)/2) * (W/nf + 0.29)'"
nrd="'0.29 / W'" nrs="'0.29 / W'"
sa=0 sb=0 sd=0
model=nfet_01v8_lvt
spiceprefix=X
}
C {sky130_fd_pr/pfet_01v8_lvt.sym} -1200 80 3 1 {name=M34
L=0.35
W=2
nf=2
mult=1
ad="'int((nf+1)/2) * W/nf * 0.29'" 
pd="'2*int((nf+1)/2) * (W/nf + 0.29)'"
as="'int((nf+2)/2) * W/nf * 0.29'" 
ps="'2*int((nf+2)/2) * (W/nf + 0.29)'"
nrd="'0.29 / W'" nrs="'0.29 / W'"
sa=0 sb=0 sd=0
model=pfet_01v8_lvt
spiceprefix=X
}
C {devices/ipin.sym} -1200 20 0 0 {name=p99 lab=n_d[6]}
C {devices/ipin.sym} -1200 400 0 0 {name=p100 lab=y_d[6]}
C {sky130_fd_pr/nfet_01v8_lvt.sym} -740 340 3 0 {name=M35
L=0.15
W=1
nf=1
mult=1
ad="'int((nf+1)/2) * W/nf * 0.29'" 
pd="'2*int((nf+1)/2) * (W/nf + 0.29)'"
as="'int((nf+2)/2) * W/nf * 0.29'" 
ps="'2*int((nf+2)/2) * (W/nf + 0.29)'"
nrd="'0.29 / W'" nrs="'0.29 / W'"
sa=0 sb=0 sd=0
model=nfet_01v8_lvt
spiceprefix=X
}
C {sky130_fd_pr/pfet_01v8_lvt.sym} -740 80 3 1 {name=M36
L=0.35
W=2
nf=2
mult=1
ad="'int((nf+1)/2) * W/nf * 0.29'" 
pd="'2*int((nf+1)/2) * (W/nf + 0.29)'"
as="'int((nf+2)/2) * W/nf * 0.29'" 
ps="'2*int((nf+2)/2) * (W/nf + 0.29)'"
nrd="'0.29 / W'" nrs="'0.29 / W'"
sa=0 sb=0 sd=0
model=pfet_01v8_lvt
spiceprefix=X
}
C {devices/ipin.sym} -740 20 0 0 {name=p113 lab=n_d[7]}
C {devices/ipin.sym} -740 400 0 0 {name=p115 lab=y_d[7]}
C {devices/lab_wire.sym} -1070 -1280 0 1 {name=p40 sig_type=std_logic lab=outpg}
C {devices/lab_wire.sym} -610 -1280 0 1 {name=p49 sig_type=std_logic lab=outpg}
C {devices/lab_wire.sym} -1070 -780 0 1 {name=p72 sig_type=std_logic lab=outpg}
C {devices/lab_wire.sym} -610 -780 0 1 {name=p81 sig_type=std_logic lab=outpg}
C {devices/lab_wire.sym} -1070 -310 0 1 {name=p90 sig_type=std_logic lab=outpg}
C {devices/lab_wire.sym} -610 -310 0 1 {name=p98 sig_type=std_logic lab=outpg}
C {devices/lab_wire.sym} -1070 190 0 1 {name=p112 sig_type=std_logic lab=outpg}
C {devices/lab_wire.sym} -610 190 0 1 {name=p119 sig_type=std_logic lab=outpg}
C {devices/lab_wire.sym} -880 -1280 0 0 {name=p48 sig_type=std_logic lab=in1}
C {devices/lab_wire.sym} -880 -780 0 0 {name=p54 sig_type=std_logic lab=in3}
C {devices/lab_wire.sym} -1340 -780 0 0 {name=p80 sig_type=std_logic lab=in2}
C {devices/lab_wire.sym} -880 -310 0 0 {name=p87 sig_type=std_logic lab=in5}
C {devices/lab_wire.sym} -1340 -310 0 0 {name=p96 sig_type=std_logic lab=in4}
C {devices/lab_wire.sym} -880 190 0 0 {name=p110 sig_type=std_logic lab=in7}
C {devices/lab_wire.sym} -1340 190 0 0 {name=p118 sig_type=std_logic lab=in6}
C {devices/lab_wire.sym} -740 -1330 1 1 {name=p15 sig_type=std_logic lab=Vdd}
C {devices/lab_wire.sym} -1200 -1330 1 1 {name=p46 sig_type=std_logic lab=Vdd}
C {devices/lab_wire.sym} -740 -1180 1 0 {name=p21 sig_type=std_logic lab=Vss}
C {devices/lab_wire.sym} -1200 -1180 1 0 {name=p47 sig_type=std_logic lab=Vss}
C {devices/lab_wire.sym} -740 -830 1 1 {name=p120 sig_type=std_logic lab=Vdd}
C {devices/lab_wire.sym} -1200 -830 1 1 {name=p121 sig_type=std_logic lab=Vdd}
C {devices/lab_wire.sym} -740 -680 1 0 {name=p122 sig_type=std_logic lab=Vss}
C {devices/lab_wire.sym} -1200 -680 1 0 {name=p123 sig_type=std_logic lab=Vss}
C {devices/lab_wire.sym} -740 -360 1 1 {name=p52 sig_type=std_logic lab=Vdd}
C {devices/lab_wire.sym} -1200 -360 1 1 {name=p53 sig_type=std_logic lab=Vdd}
C {devices/lab_wire.sym} -740 -210 1 0 {name=p77 sig_type=std_logic lab=Vss}
C {devices/lab_wire.sym} -1200 -210 1 0 {name=p78 sig_type=std_logic lab=Vss}
C {devices/lab_wire.sym} -740 140 1 1 {name=p84 sig_type=std_logic lab=Vdd}
C {devices/lab_wire.sym} -1200 140 1 1 {name=p86 sig_type=std_logic lab=Vdd}
C {devices/lab_wire.sym} -740 290 1 0 {name=p93 sig_type=std_logic lab=Vss}
C {devices/lab_wire.sym} -1200 290 1 0 {name=p94 sig_type=std_logic lab=Vss}
